VERSION 5.7 ;
BUSBITCHARS "[]" ;
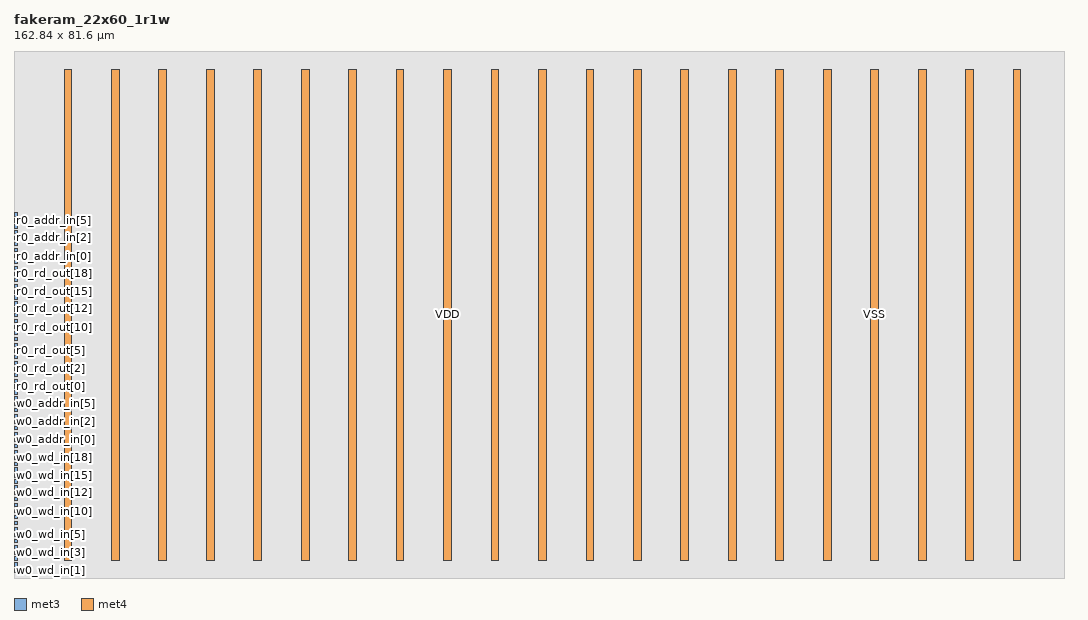
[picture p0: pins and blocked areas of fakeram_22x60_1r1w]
MACRO fakeram_22x60_1r1w
  FOREIGN fakeram_22x60_1r1w 0 0 ;
  SYMMETRY X Y R90 ;
  SIZE 162.840 BY 81.600 ;
  CLASS BLOCK ;
  PIN w0_wd_in[0]
    DIRECTION INPUT ;
    USE SIGNAL ;
    SHAPE ABUTMENT ;
    PORT
      LAYER met3 ;
      RECT 0.000 0.920 0.500 1.420 ;
    END
  END w0_wd_in[0]
  PIN w0_wd_in[1]
    DIRECTION INPUT ;
    USE SIGNAL ;
    SHAPE ABUTMENT ;
    PORT
      LAYER met3 ;
      RECT 0.000 1.840 0.500 2.340 ;
    END
  END w0_wd_in[1]
  PIN w0_wd_in[2]
    DIRECTION INPUT ;
    USE SIGNAL ;
    SHAPE ABUTMENT ;
    PORT
      LAYER met3 ;
      RECT 0.000 2.760 0.500 3.260 ;
    END
  END w0_wd_in[2]
  PIN w0_wd_in[3]
    DIRECTION INPUT ;
    USE SIGNAL ;
    SHAPE ABUTMENT ;
    PORT
      LAYER met3 ;
      RECT 0.000 3.680 0.500 4.180 ;
    END
  END w0_wd_in[3]
  PIN w0_wd_in[4]
    DIRECTION INPUT ;
    USE SIGNAL ;
    SHAPE ABUTMENT ;
    PORT
      LAYER met3 ;
      RECT 0.000 4.600 0.500 5.100 ;
    END
  END w0_wd_in[4]
  PIN w0_wd_in[5]
    DIRECTION INPUT ;
    USE SIGNAL ;
    SHAPE ABUTMENT ;
    PORT
      LAYER met3 ;
      RECT 0.000 5.520 0.500 6.020 ;
    END
  END w0_wd_in[5]
  PIN w0_wd_in[6]
    DIRECTION INPUT ;
    USE SIGNAL ;
    SHAPE ABUTMENT ;
    PORT
      LAYER met3 ;
      RECT 0.000 6.440 0.500 6.940 ;
    END
  END w0_wd_in[6]
  PIN w0_wd_in[7]
    DIRECTION INPUT ;
    USE SIGNAL ;
    SHAPE ABUTMENT ;
    PORT
      LAYER met3 ;
      RECT 0.000 7.360 0.500 7.860 ;
    END
  END w0_wd_in[7]
  PIN w0_wd_in[8]
    DIRECTION INPUT ;
    USE SIGNAL ;
    SHAPE ABUTMENT ;
    PORT
      LAYER met3 ;
      RECT 0.000 8.280 0.500 8.780 ;
    END
  END w0_wd_in[8]
  PIN w0_wd_in[9]
    DIRECTION INPUT ;
    USE SIGNAL ;
    SHAPE ABUTMENT ;
    PORT
      LAYER met3 ;
      RECT 0.000 9.200 0.500 9.700 ;
    END
  END w0_wd_in[9]
  PIN w0_wd_in[10]
    DIRECTION INPUT ;
    USE SIGNAL ;
    SHAPE ABUTMENT ;
    PORT
      LAYER met3 ;
      RECT 0.000 10.120 0.500 10.620 ;
    END
  END w0_wd_in[10]
  PIN w0_wd_in[11]
    DIRECTION INPUT ;
    USE SIGNAL ;
    SHAPE ABUTMENT ;
    PORT
      LAYER met3 ;
      RECT 0.000 11.040 0.500 11.540 ;
    END
  END w0_wd_in[11]
  PIN w0_wd_in[12]
    DIRECTION INPUT ;
    USE SIGNAL ;
    SHAPE ABUTMENT ;
    PORT
      LAYER met3 ;
      RECT 0.000 11.960 0.500 12.460 ;
    END
  END w0_wd_in[12]
  PIN w0_wd_in[13]
    DIRECTION INPUT ;
    USE SIGNAL ;
    SHAPE ABUTMENT ;
    PORT
      LAYER met3 ;
      RECT 0.000 12.880 0.500 13.380 ;
    END
  END w0_wd_in[13]
  PIN w0_wd_in[14]
    DIRECTION INPUT ;
    USE SIGNAL ;
    SHAPE ABUTMENT ;
    PORT
      LAYER met3 ;
      RECT 0.000 13.800 0.500 14.300 ;
    END
  END w0_wd_in[14]
  PIN w0_wd_in[15]
    DIRECTION INPUT ;
    USE SIGNAL ;
    SHAPE ABUTMENT ;
    PORT
      LAYER met3 ;
      RECT 0.000 14.720 0.500 15.220 ;
    END
  END w0_wd_in[15]
  PIN w0_wd_in[16]
    DIRECTION INPUT ;
    USE SIGNAL ;
    SHAPE ABUTMENT ;
    PORT
      LAYER met3 ;
      RECT 0.000 15.640 0.500 16.140 ;
    END
  END w0_wd_in[16]
  PIN w0_wd_in[17]
    DIRECTION INPUT ;
    USE SIGNAL ;
    SHAPE ABUTMENT ;
    PORT
      LAYER met3 ;
      RECT 0.000 16.560 0.500 17.060 ;
    END
  END w0_wd_in[17]
  PIN w0_wd_in[18]
    DIRECTION INPUT ;
    USE SIGNAL ;
    SHAPE ABUTMENT ;
    PORT
      LAYER met3 ;
      RECT 0.000 17.480 0.500 17.980 ;
    END
  END w0_wd_in[18]
  PIN w0_wd_in[19]
    DIRECTION INPUT ;
    USE SIGNAL ;
    SHAPE ABUTMENT ;
    PORT
      LAYER met3 ;
      RECT 0.000 18.400 0.500 18.900 ;
    END
  END w0_wd_in[19]
  PIN w0_wd_in[20]
    DIRECTION INPUT ;
    USE SIGNAL ;
    SHAPE ABUTMENT ;
    PORT
      LAYER met3 ;
      RECT 0.000 19.320 0.500 19.820 ;
    END
  END w0_wd_in[20]
  PIN w0_wd_in[21]
    DIRECTION INPUT ;
    USE SIGNAL ;
    SHAPE ABUTMENT ;
    PORT
      LAYER met3 ;
      RECT 0.000 20.240 0.500 20.740 ;
    END
  END w0_wd_in[21]
  PIN w0_addr_in[0]
    DIRECTION INPUT ;
    USE SIGNAL ;
    SHAPE ABUTMENT ;
    PORT
      LAYER met3 ;
      RECT 0.000 21.160 0.500 21.660 ;
    END
  END w0_addr_in[0]
  PIN w0_addr_in[1]
    DIRECTION INPUT ;
    USE SIGNAL ;
    SHAPE ABUTMENT ;
    PORT
      LAYER met3 ;
      RECT 0.000 22.080 0.500 22.580 ;
    END
  END w0_addr_in[1]
  PIN w0_addr_in[2]
    DIRECTION INPUT ;
    USE SIGNAL ;
    SHAPE ABUTMENT ;
    PORT
      LAYER met3 ;
      RECT 0.000 23.000 0.500 23.500 ;
    END
  END w0_addr_in[2]
  PIN w0_addr_in[3]
    DIRECTION INPUT ;
    USE SIGNAL ;
    SHAPE ABUTMENT ;
    PORT
      LAYER met3 ;
      RECT 0.000 23.920 0.500 24.420 ;
    END
  END w0_addr_in[3]
  PIN w0_addr_in[4]
    DIRECTION INPUT ;
    USE SIGNAL ;
    SHAPE ABUTMENT ;
    PORT
      LAYER met3 ;
      RECT 0.000 24.840 0.500 25.340 ;
    END
  END w0_addr_in[4]
  PIN w0_addr_in[5]
    DIRECTION INPUT ;
    USE SIGNAL ;
    SHAPE ABUTMENT ;
    PORT
      LAYER met3 ;
      RECT 0.000 25.760 0.500 26.260 ;
    END
  END w0_addr_in[5]
  PIN w0_clk
    DIRECTION INPUT ;
    USE SIGNAL ;
    SHAPE ABUTMENT ;
    PORT
      LAYER met3 ;
      RECT 0.000 26.680 0.500 27.180 ;
    END
  END w0_clk
  PIN w0_ce_in
    DIRECTION INPUT ;
    USE SIGNAL ;
    SHAPE ABUTMENT ;
    PORT
      LAYER met3 ;
      RECT 0.000 27.600 0.500 28.100 ;
    END
  END w0_ce_in
  PIN w0_we_in
    DIRECTION INPUT ;
    USE SIGNAL ;
    SHAPE ABUTMENT ;
    PORT
      LAYER met3 ;
      RECT 0.000 28.520 0.500 29.020 ;
    END
  END w0_we_in
  PIN r0_rd_out[0]
    DIRECTION OUTPUT ;
    USE SIGNAL ;
    SHAPE ABUTMENT ;
    PORT
      LAYER met3 ;
      RECT 0.000 29.440 0.500 29.940 ;
    END
  END r0_rd_out[0]
  PIN r0_rd_out[1]
    DIRECTION OUTPUT ;
    USE SIGNAL ;
    SHAPE ABUTMENT ;
    PORT
      LAYER met3 ;
      RECT 0.000 30.360 0.500 30.860 ;
    END
  END r0_rd_out[1]
  PIN r0_rd_out[2]
    DIRECTION OUTPUT ;
    USE SIGNAL ;
    SHAPE ABUTMENT ;
    PORT
      LAYER met3 ;
      RECT 0.000 31.280 0.500 31.780 ;
    END
  END r0_rd_out[2]
  PIN r0_rd_out[3]
    DIRECTION OUTPUT ;
    USE SIGNAL ;
    SHAPE ABUTMENT ;
    PORT
      LAYER met3 ;
      RECT 0.000 32.200 0.500 32.700 ;
    END
  END r0_rd_out[3]
  PIN r0_rd_out[4]
    DIRECTION OUTPUT ;
    USE SIGNAL ;
    SHAPE ABUTMENT ;
    PORT
      LAYER met3 ;
      RECT 0.000 33.120 0.500 33.620 ;
    END
  END r0_rd_out[4]
  PIN r0_rd_out[5]
    DIRECTION OUTPUT ;
    USE SIGNAL ;
    SHAPE ABUTMENT ;
    PORT
      LAYER met3 ;
      RECT 0.000 34.040 0.500 34.540 ;
    END
  END r0_rd_out[5]
  PIN r0_rd_out[6]
    DIRECTION OUTPUT ;
    USE SIGNAL ;
    SHAPE ABUTMENT ;
    PORT
      LAYER met3 ;
      RECT 0.000 34.960 0.500 35.460 ;
    END
  END r0_rd_out[6]
  PIN r0_rd_out[7]
    DIRECTION OUTPUT ;
    USE SIGNAL ;
    SHAPE ABUTMENT ;
    PORT
      LAYER met3 ;
      RECT 0.000 35.880 0.500 36.380 ;
    END
  END r0_rd_out[7]
  PIN r0_rd_out[8]
    DIRECTION OUTPUT ;
    USE SIGNAL ;
    SHAPE ABUTMENT ;
    PORT
      LAYER met3 ;
      RECT 0.000 36.800 0.500 37.300 ;
    END
  END r0_rd_out[8]
  PIN r0_rd_out[9]
    DIRECTION OUTPUT ;
    USE SIGNAL ;
    SHAPE ABUTMENT ;
    PORT
      LAYER met3 ;
      RECT 0.000 37.720 0.500 38.220 ;
    END
  END r0_rd_out[9]
  PIN r0_rd_out[10]
    DIRECTION OUTPUT ;
    USE SIGNAL ;
    SHAPE ABUTMENT ;
    PORT
      LAYER met3 ;
      RECT 0.000 38.640 0.500 39.140 ;
    END
  END r0_rd_out[10]
  PIN r0_rd_out[11]
    DIRECTION OUTPUT ;
    USE SIGNAL ;
    SHAPE ABUTMENT ;
    PORT
      LAYER met3 ;
      RECT 0.000 39.560 0.500 40.060 ;
    END
  END r0_rd_out[11]
  PIN r0_rd_out[12]
    DIRECTION OUTPUT ;
    USE SIGNAL ;
    SHAPE ABUTMENT ;
    PORT
      LAYER met3 ;
      RECT 0.000 40.480 0.500 40.980 ;
    END
  END r0_rd_out[12]
  PIN r0_rd_out[13]
    DIRECTION OUTPUT ;
    USE SIGNAL ;
    SHAPE ABUTMENT ;
    PORT
      LAYER met3 ;
      RECT 0.000 41.400 0.500 41.900 ;
    END
  END r0_rd_out[13]
  PIN r0_rd_out[14]
    DIRECTION OUTPUT ;
    USE SIGNAL ;
    SHAPE ABUTMENT ;
    PORT
      LAYER met3 ;
      RECT 0.000 42.320 0.500 42.820 ;
    END
  END r0_rd_out[14]
  PIN r0_rd_out[15]
    DIRECTION OUTPUT ;
    USE SIGNAL ;
    SHAPE ABUTMENT ;
    PORT
      LAYER met3 ;
      RECT 0.000 43.240 0.500 43.740 ;
    END
  END r0_rd_out[15]
  PIN r0_rd_out[16]
    DIRECTION OUTPUT ;
    USE SIGNAL ;
    SHAPE ABUTMENT ;
    PORT
      LAYER met3 ;
      RECT 0.000 44.160 0.500 44.660 ;
    END
  END r0_rd_out[16]
  PIN r0_rd_out[17]
    DIRECTION OUTPUT ;
    USE SIGNAL ;
    SHAPE ABUTMENT ;
    PORT
      LAYER met3 ;
      RECT 0.000 45.080 0.500 45.580 ;
    END
  END r0_rd_out[17]
  PIN r0_rd_out[18]
    DIRECTION OUTPUT ;
    USE SIGNAL ;
    SHAPE ABUTMENT ;
    PORT
      LAYER met3 ;
      RECT 0.000 46.000 0.500 46.500 ;
    END
  END r0_rd_out[18]
  PIN r0_rd_out[19]
    DIRECTION OUTPUT ;
    USE SIGNAL ;
    SHAPE ABUTMENT ;
    PORT
      LAYER met3 ;
      RECT 0.000 46.920 0.500 47.420 ;
    END
  END r0_rd_out[19]
  PIN r0_rd_out[20]
    DIRECTION OUTPUT ;
    USE SIGNAL ;
    SHAPE ABUTMENT ;
    PORT
      LAYER met3 ;
      RECT 0.000 47.840 0.500 48.340 ;
    END
  END r0_rd_out[20]
  PIN r0_rd_out[21]
    DIRECTION OUTPUT ;
    USE SIGNAL ;
    SHAPE ABUTMENT ;
    PORT
      LAYER met3 ;
      RECT 0.000 48.760 0.500 49.260 ;
    END
  END r0_rd_out[21]
  PIN r0_addr_in[0]
    DIRECTION INPUT ;
    USE SIGNAL ;
    SHAPE ABUTMENT ;
    PORT
      LAYER met3 ;
      RECT 0.000 49.680 0.500 50.180 ;
    END
  END r0_addr_in[0]
  PIN r0_addr_in[1]
    DIRECTION INPUT ;
    USE SIGNAL ;
    SHAPE ABUTMENT ;
    PORT
      LAYER met3 ;
      RECT 0.000 50.600 0.500 51.100 ;
    END
  END r0_addr_in[1]
  PIN r0_addr_in[2]
    DIRECTION INPUT ;
    USE SIGNAL ;
    SHAPE ABUTMENT ;
    PORT
      LAYER met3 ;
      RECT 0.000 51.520 0.500 52.020 ;
    END
  END r0_addr_in[2]
  PIN r0_addr_in[3]
    DIRECTION INPUT ;
    USE SIGNAL ;
    SHAPE ABUTMENT ;
    PORT
      LAYER met3 ;
      RECT 0.000 52.440 0.500 52.940 ;
    END
  END r0_addr_in[3]
  PIN r0_addr_in[4]
    DIRECTION INPUT ;
    USE SIGNAL ;
    SHAPE ABUTMENT ;
    PORT
      LAYER met3 ;
      RECT 0.000 53.360 0.500 53.860 ;
    END
  END r0_addr_in[4]
  PIN r0_addr_in[5]
    DIRECTION INPUT ;
    USE SIGNAL ;
    SHAPE ABUTMENT ;
    PORT
      LAYER met3 ;
      RECT 0.000 54.280 0.500 54.780 ;
    END
  END r0_addr_in[5]
  PIN r0_clk
    DIRECTION INPUT ;
    USE SIGNAL ;
    SHAPE ABUTMENT ;
    PORT
      LAYER met3 ;
      RECT 0.000 55.200 0.500 55.700 ;
    END
  END r0_clk
  PIN r0_ce_in
    DIRECTION INPUT ;
    USE SIGNAL ;
    SHAPE ABUTMENT ;
    PORT
      LAYER met3 ;
      RECT 0.000 56.120 0.500 56.620 ;
    END
  END r0_ce_in
  PIN VDD
    DIRECTION INOUT ;
    USE POWER ;
    PORT
      LAYER met4 ;
      RECT 7.760 2.720 8.960 78.880 ;
      RECT 22.480 2.720 23.680 78.880 ;
      RECT 37.200 2.720 38.400 78.880 ;
      RECT 51.920 2.720 53.120 78.880 ;
      RECT 66.640 2.720 67.840 78.880 ;
      RECT 81.360 2.720 82.560 78.880 ;
      RECT 96.080 2.720 97.280 78.880 ;
      RECT 110.800 2.720 112.000 78.880 ;
      RECT 125.520 2.720 126.720 78.880 ;
      RECT 140.240 2.720 141.440 78.880 ;
      RECT 154.960 2.720 156.160 78.880 ;
    END
  END VDD
  PIN VSS
    DIRECTION INOUT ;
    USE GROUND ;
    PORT
      LAYER met4 ;
      RECT 15.120 2.720 16.320 78.880 ;
      RECT 29.840 2.720 31.040 78.880 ;
      RECT 44.560 2.720 45.760 78.880 ;
      RECT 59.280 2.720 60.480 78.880 ;
      RECT 74.000 2.720 75.200 78.880 ;
      RECT 88.720 2.720 89.920 78.880 ;
      RECT 103.440 2.720 104.640 78.880 ;
      RECT 118.160 2.720 119.360 78.880 ;
      RECT 132.880 2.720 134.080 78.880 ;
      RECT 147.600 2.720 148.800 78.880 ;
    END
  END VSS
  OBS
    LAYER met1 ;
      RECT 0.000 0.000 162.840 81.600 ;
    LAYER met2 ;
      RECT 0.000 0.000 162.840 81.600 ;
    LAYER met3 ;
      RECT 0.000 0.000 162.840 81.600 ;
  END
END fakeram_22x60_1r1w
END LIBRARY
